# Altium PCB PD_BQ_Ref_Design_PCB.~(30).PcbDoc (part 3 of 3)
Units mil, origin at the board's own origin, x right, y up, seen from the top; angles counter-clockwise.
Board outline 2000 x 3702.76 mil, 4 copper layers (Top Layer, Signal Layer 1, Signal Layer 2, Bottom Layer), stack 61.2 mil thick; 124 components, 53 nets, 359 pads, 494 vias.
Unrouted connection lines stored in the file: 227.

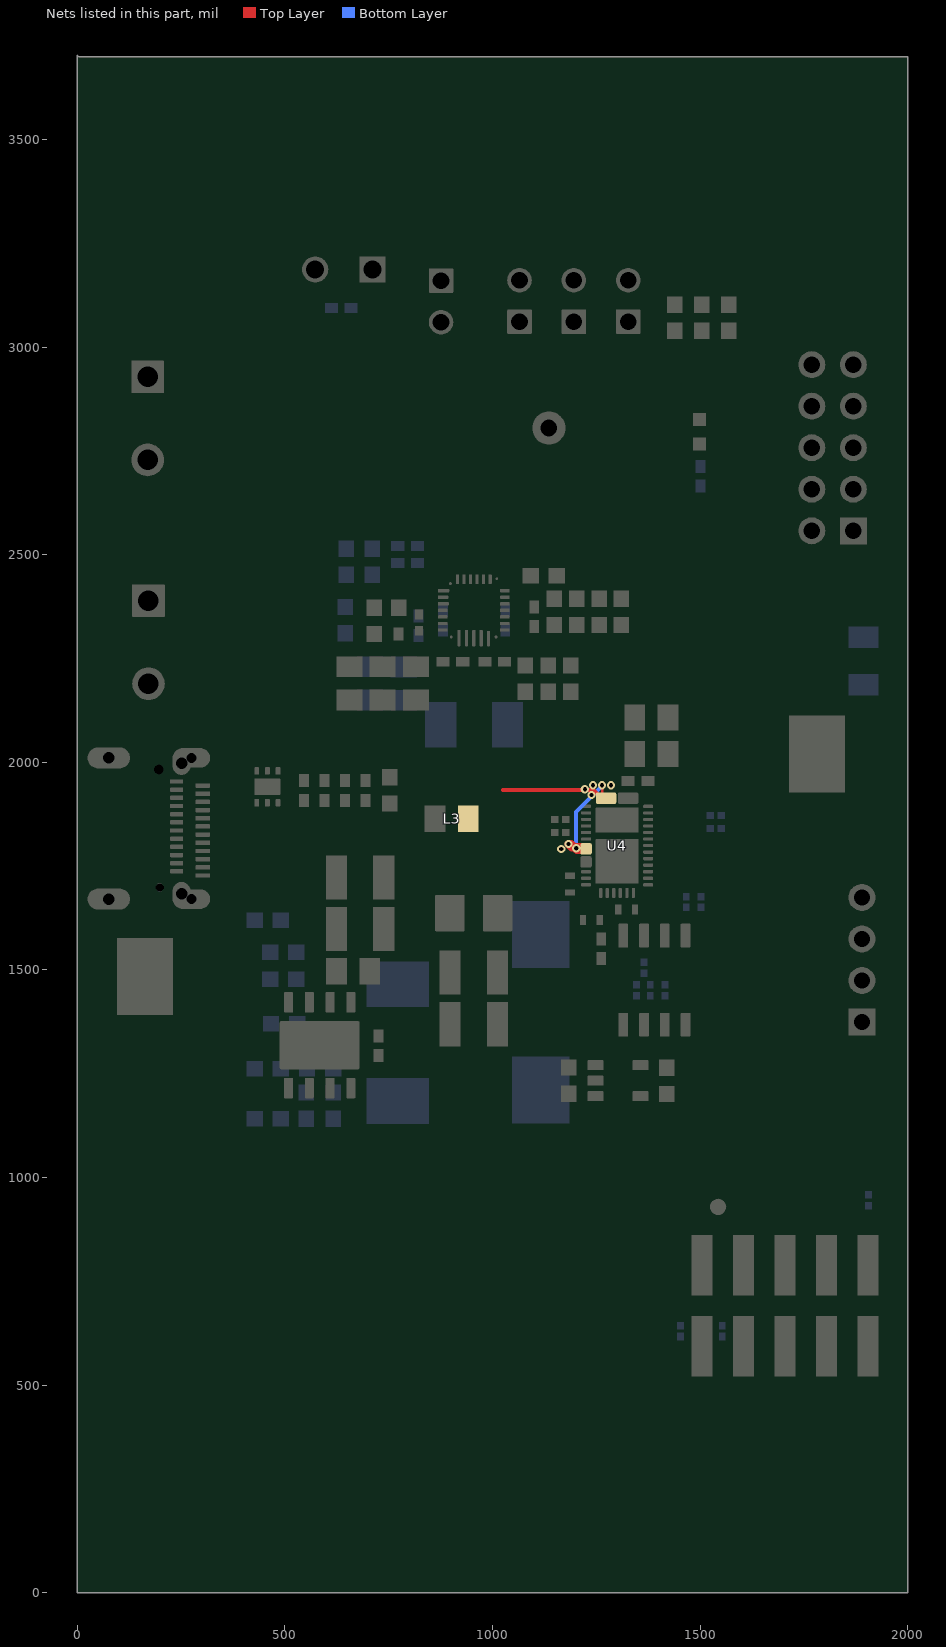
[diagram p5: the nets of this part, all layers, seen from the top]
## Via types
v1: diameter 20, hole 10, Top Layer to Bottom Layer, tented both sides, 445 vias
v2: diameter 23.62, hole 11.81, Top Layer to Bottom Layer, 24 vias
v3: diameter 30, hole 15, Top Layer to Bottom Layer, tented both sides, 12 vias
v4: diameter 19.68, hole 7.87, Top Layer to Bottom Layer, tented both sides, 10 vias
v5: diameter 20, hole 10, Top Layer to Bottom Layer, 3 vias

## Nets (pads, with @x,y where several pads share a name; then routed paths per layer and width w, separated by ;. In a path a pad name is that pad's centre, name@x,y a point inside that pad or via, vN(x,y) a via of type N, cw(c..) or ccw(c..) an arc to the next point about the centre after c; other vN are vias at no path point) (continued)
VBUS: L3.2 U4.23 U4.24 U4.25 U4.32 U4.33 U4.@1225.2,1791.52 U4.@1273.37,1913.57 | length 575.9
  Top Layer w6: v1@1200.79,1791.34 1225.02,1791.34 U4.@1225.2,1791.52 ; v1(1263.78,1944.88) 1263.78,1923.66 1273.62,1913.81 U4.@1273.37,1913.57
  Top Layer w10: 1025.59,1933.07 1222.44,1933.07 1242.98,1933.07 1262.49,1913.57 U4.@1273.37,1913.57
  Top Layer w20: v1@1210.63,1788.8 1203.32,1788.8 v1@1196.83,1795.3 ; U4.@1225.2,1791.52 1221.43,1795.3 v1@1196.83,1795.3 ; v1@1196.83,1795.3 1188.98,1803.15 v1(1183.07,1803.15) 1190.92,1795.3 v1@1196.83,1795.3
  Bottom Layer w10: v1@1200.79,1791.34 1200.79,1879.92 1263.78,1942.91 v1(1263.78,1944.88)
  other v1: 1165.35,1791.34 1201.76,1792.84 1238.19,1921.26 1222.44,1935.04 1242.13,1944.88 1285.43,1944.88
pads on no net: FID1.1 FID2.1 FID3.1 FID4.1 FID5.1 FID6.1 H1.1 H2.1 H3.1 H4.1 H5.0 H6.0 H7.0 H8.0 J3.1 J3.2 J3.3 J3.4 J3.7 J3.8 J5.4 J5.5 J5.6 J5.7 J5.8 J5.9 J6.A2 J6.A3 J6.A8 J6.A10 J6.A11 J6.ALIGN1 J6.ALIGN2 J6.B2 J6.B3 J6.B8 J6.B10 J6.B11 J7.1 SH-J1.0 SH-J2.0 U1.6 U1.7 U1.12 U1.21 U2.4 U3.9@583.66,1318.62 U4.6 U4.7 U4.13 U4.19 U4.36 U4.37 U6.7@439.96,1940.94 U6.7@475.39,1940.94

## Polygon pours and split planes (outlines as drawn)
NetC22_1 on Top Layer "TOP_LAYER_NETC22_1_P111" (solid, remove dead copper, pour order 111): 904.78,2306.69 854.73,2306.69 854.33,2307.09 854.33,2277.56 905.51,2277.56 904.78,2278.29
STAT on Top Layer "TOP_LAYER_STAT_P109" (solid, remove dead copper, pour order 109): 1003.94,2306.69 1003.94,2280.91 1005.32,2279.53 1041.34,2279.53 1041.34,2306.63 1040.88,2307.09 1040.2,2306.41 1004.63,2306.41
PPHV on Top Layer "TOP_LAYER_PPHV_P107" (solid, remove dead copper, pour order 107): 1006.6,2425.67 1006.17,2426.1 1006.17,2470.47 1045.28,2491.1 1046.22,2490.16 1055.12,2490.16 1055.12,2478.35 1039.37,2462.6 1039.37,2411.42 1041.14,2409.65 1019.69,2409.65 1019.69,2423.23 1017.24,2425.67
TS on Top Layer "TOP_LAYER_TS_P105" (solid, remove dead copper, pour order 105): 858.27,2462.6 891.62,2462.6 903.54,2450.67 903.54,2425.67 869.36,2425.67 869.08,2425.4 859.44,2435.04 858.27,2435.04
NetC1_2 on Top Layer "TOP_LAYER_NETC1_2_P103" (solid, remove dead copper, pour order 103): 966.54,2364.17 966.54,2322.83 1013.78,2322.83 1013.78,2364.17
NetC7_2 on Top Layer "TOP_LAYER_NETC7_2_P101" (solid, remove dead copper, pour order 101): 899.61,2364.17 899.61,2324.8 942.91,2324.8 942.91,2364.17
BAT on Top Layer "TOP_LAYER_BAT_P099" (solid, pour order 99): 775.59,2330.71 842.52,2330.71 842.52,2316.93 840.55,2314.96 775.59,2314.96 775.59,2330.47 775.35,2330.71
GND on Top Layer "tgaTOP_LAYER_GND_P081" (solid, pour order 97): 14.09,159.45 2014.09,159.45 2014.09,3507.87 14.09,3507.87
VBUS on Top Layer "Top Layer-VBUS" (solid, pour order 95): 1104.33,1929.13 1206.69,1929.13 1236.22,1899.61 1297.24,1899.61 1297.24,1994.09 1025.59,1994.09 956.69,1925.2 911.42,1925.2 911.42,1799.21 974.41,1799.21
NetC44_1 on Top Layer "Top Layer-NetC44_1" (solid, pour order 89): 433.07,1799.21 891.73,1799.21 891.73,1842.52 891.73,1925.2 793.31,1925.2 505.91,1925.2 494.09,1913.39 421.26,1913.39 397.64,1889.76 330.71,1889.76 330.71,1781.5 415.35,1781.5
SYS on Top Layer "Top Layer-SYS" (solid, pour order 40): 547.24,1527.56 596.46,1478.35 596.46,1433.07 620.08,1433.07 651.57,1464.57 655.51,1464.57 655.51,1779.53 464.57,1779.53 464.57,1669.29 547.24,1669.29
NetC25_2 on Top Layer "Top Layer-NetC25_2" (solid, pour order 85): 692.91,1204.72 728.35,1204.72 777.56,1253.94 777.56,1309.06 692.91,1309.06
SYS on Top Layer "Top Layer-SYS 1" (solid, pour order 72): 261.81,2187.01 865.07,2187.01 906.41,2228.35 906.41,2275.59 557.09,2275.59 535.43,2297.24 303.15,2297.24 224.41,2375.98 224.41,2444.88 202.76,2444.88 118.11,2444.88 118.11,2330.71
LDO_1V5 on Top Layer "NONET_L-01_P-001" (solid, pour order 77): 1273.62,1673.23 1273.62,1696.85 1311.02,1696.85 1311.02,1633.86 1295.28,1633.86 1295.28,1651.57
AGND on Top Layer "NONET_L-01_P-001" (solid, pour order 76): 1407.48,3066.93 1604.33,3066.93 1604.33,2988.19 1407.48,2988.19
AGND on Top Layer "NONET_L-01_P-001" (solid, pour order 75): 952.76,2429.13 940.94,2429.13 940.94,2490.16 1000,2490.16 1000,2429.13 972.44,2429.13 972.44,2456.69 952.76,2456.69
BAT on Top Layer "Top Layer-BAT" (solid, pour order 66): 565.01,2287.35 655.51,2287.4 832.68,2287.4 860.24,2314.96 889.76,2314.96 889.76,2338.58 852.36,2338.58 832.68,2318.9 803.15,2318.9 791.34,2330.71 694.88,2330.71 527.56,2498.03 527.56,2580.71 311.56,2796.71 110.24,2796.71 110.24,2673.23 281.5,2673.23 419.29,2535.43 419.29,2433.07
PPHV on Top Layer "Top Layer-PPHV" (solid, pour order 51): 1275.59,1899.61 1352.36,1899.61 1352.36,1980.32 1383.86,2011.81 1383.86,2181.1 1383.86,2364.17 1049.21,2364.17 1049.21,2287.4 1238.19,2287.4 1275.59,2250
no net on Top Layer "NONET_L-01_P-001" (solid, pour order 49): 1383.86,2181.1
no net on Top Layer "NONET_L-01_P-001" (solid, pour order 48): 1383.86,2161.42
PPHV on Top Layer "NONET_L-01_P-001" (solid, pour order 14): 1096.89,2338.58 1122.32,2364.02 1330.61,2364.02 1330.78,2309.06 1018.82,2309.06 1018.82,2338.58
REGN on Top Layer "NONET_L-01_P-001" (solid, pour order 32): 1026.69,2362.2 1054.25,2362.2 1081.81,2389.76 1081.81,2401.57 1111.34,2431.1 1111.34,2468.5 1071.97,2468.5 1052.28,2448.82 1052.28,2379.92 1042.44,2370.08 1026.69,2370.08
PMID on Top Layer "NONET_L-01_P-001" (solid, pour order 42): 1005.04,2275.59 1238.19,2275.59 1238.19,2200.79 1032.6,2200.79 1005.04,2228.35
P3V3 on Top Layer "NONET_L-01_P-001" (solid, pour order 30): 1212.6,1708.66 1198.82,1694.88 1198.82,1679.13 1206.69,1679.13 1228.35,1700.79 1228.35,1708.66
VBUS on Top Layer "NONET_L-01_P-001" (solid, pour order 20): 1218.5,1777.56 1218.5,1805.12 1200.79,1805.12 1188.98,1816.93 1149.61,1816.93 1149.61,1777.56
LDO_1V5 on Top Layer "NONET_L-01_P-001" (solid, pour order 31): 1311.02,1624.02 1311.02,1688.98 1273.62,1688.98 1273.62,1673.23 1293.31,1673.23 1293.31,1624.02
LDO_3V3 on Top Layer "NONET_L-01_P-001" (solid, pour order 29): 1265.75,1681.1 1271.65,1675.2 1271.65,1622.05 1251.97,1622.05 1251.97,1649.61 1251.97,1681.1
PP5V on Top Layer "NONET_L-01_P-001" (solid, pour order 28): 1263.78,1685.04
PP5V on Top Layer "Top Layer-PP5V" (solid, pour order 17): 970.47,1295.28 1110.24,1295.28 1110.24,1710.63 1145.67,1746.06 1238.19,1746.06 1238.19,1773.62 1157.48,1773.62 1137.61,1793.49 1039.55,1793.49 1017.72,1771.65 970.47,1724.41
NetC1_2 on Bottom Layer "NONET_L-01_P-001" (solid, pour order 44): 1000,2037.4 1000,2141.73 1044.41,2141.73 1044.41,2037.4
NetC7_2 on Bottom Layer "NONET_L-01_P-001" (solid, pour order 43): 913.39,2037.4 913.39,2141.73 867.24,2141.73 867.24,2037.4
GND on Bottom Layer "BOTTOM_LAYER_GND_P090" (solid, remove dead copper, pour order 90): -9.77,342.38 1990.23,342.38 1990.23,3342.38 -9.77,3342.38
SYS on Bottom Layer "Top Layer-SYS 1" (solid, pour order 87): 500,2187.01 865.07,2187.01 906.41,2228.35 906.41,2275.59 557.09,2275.59 535.43,2297.24 500,2297.24
SYS on Bottom Layer "Bottom Layer-SYS" (solid, pour order 74): 610.24,1881.89 610.24,2033.46 610.24,2277.56 500,2277.56 500,1984.25 500,1921.26 464.57,1885.83 464.57,1669.29 574.8,1669.29 574.8,1846.46
NetC25_2 on Bottom Layer "Bottom Layer-NetC25_2" (solid, pour order 84): 692.91,1125.98 960.63,1125.98 1187.01,1125.98 1187.01,1242.13 777.56,1242.13 777.56,1309.06 692.91,1309.06
NetU4_15 on Bottom Layer "NONET_L-01_P-001" (solid, pour order 78): 1247.84,1891.73 1247.84,1829.91 1352.05,1829.91 1352.37,1891.73
no net on Bottom Layer "NONET_L-01_P-001" (solid, pour order 37): 539.37,2372.05
PP5V on Bottom Layer "NONET_L-01_P-001" (solid, pour order 22): 970.47,1665.35 970.47,1446.85 1185.04,1446.85 1185.04,1665.35
VBUS on Bottom Layer "NONET_L-01_P-001" (solid, pour order 21): 1212.6,1777.56 1157.48,1777.56 1157.48,1891.73 1222.44,1956.69 1297.24,1956.69 1297.24,1899.61 1238.19,1899.61 1212.6,1874.02
AGND on Signal Layer 2 "SIGNAL_LAYER_2_AGND_P083" (solid, remove dead copper, pour order 83): 5.91,330.71 2005.91,330.71 2005.91,3330.71 5.91,3330.71
NetU4_15 on Signal Layer 2 "NONET_L-01_P-001" (solid, pour order 80): 1248.03,1890.37 1248.03,1830.71 1352.24,1830.89 1352.36,1890.37
NetC7_2 on Signal Layer 2 "NONET_L-01_P-001" (solid, pour order 45): 900.71,2218.5 873.15,2218.5 873.15,2250 900.71,2277.56 900.71,2354.33 942.05,2354.33 942.05,2261.81
NetC1_2 on Signal Layer 2 "NONET_L-01_P-001" (solid, pour order 46): 1010.94,2218.5 1038.5,2218.5 1038.5,2250 1010.94,2277.56 1010.94,2354.33 969.61,2354.33 969.61,2261.81
GND on Signal Layer 1 "SIGNAL_LAYER_1_GND_P082" (solid, pour order 82): 5.91,330.71 2005.91,330.71 2005.91,3330.71 5.91,3330.71
NetU4_15 on Signal Layer 1 "NONET_L-01_P-001" (solid, pour order 79): 1248.03,1891.73 1352.36,1891.73 1351.98,1891.35 1351.98,1830.89 1248.04,1830.89

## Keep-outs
Keep-Out Layer:
  text ".Layer_Name" at 582.91,-527.78 h60

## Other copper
Top Layer:
  pour cut-out: 1005.91,2029.53 1005.91,2149.61 905.51,2149.61 905.51,2029.53
  text ".Layer_Name" at 582.91,-527.78 h60
Signal Layer 1:
  pour cut-out: 860.24,2151.57 1051.18,2151.57 1051.18,2029.53 862.2,2029.53
Signal Layer 2:
  pour cut-out: 860.24,2188.98 1051.18,2188.98 1051.18,2027.56 862.2,2027.56
Bottom Layer:
  pour cut-out: 860.24,2153.54 860.24,2027.56 1051.18,2027.56 1051.18,2153.54
  text ".Layer_Name" at 582.91,-527.78 h60

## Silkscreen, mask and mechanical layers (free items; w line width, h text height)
Top Overlay:
  lines w5: 392.72,1996.06 392.72,2104.33 392.72,2549.21 1243.11,2549.21 1498.03,2549.21 1498.03,1096.46 392.72,1096.46 392.72,1275.59 392.72,1999.02 ; 836.61,2025.59 852.36,2041.34 866.14,2055.12 866.14,2196.85 879.92,2210.63 ; 1033.46,2210.63 1043.31,2200.79 1043.31,2055.12 1068.9,2029.53 1075.79,2022.64 ; 1120.08,2295.28 1133.86,2281.5 1248.03,2281.5 ; 1188.98,2429.13 1210.63,2450.79 ; 1220.47,2429.13 1244.09,2452.76 ; 1267.72,2429.13 1293.31,2454.72 ; 1320.87,2431.1 1346.46,2456.69 ; 1210.63,2450.79 1210.63,2450.79
  text "'.PRJ_Number'.PCB_Rev" at 1427.17,3212.6 h108.27
  text "up to 5A" at 51.18,3051.18 h60
  text "EXT_TS" at 548.34,2978.23 h60
  text "2S" at 1047.62,2960.77 h60
  text "4S" at 1312.12,2959.76 h60
  text "3S" at 1179.51,2959.17 h60
  text "TS" at 855.43,2953.85 h60
  text "GND" at 431.98,2859.36 h60 r90
  text "STAT" at 1302.28,2818.02 h60
  text "PPHV" at 1064.09,2644.8 h60
  text "BATT" at 443.79,2627.08 h60 r90
  text "up to 10A" at 59.06,2515.93 h60
  text "SYS" at 447.72,2341.65 h60 r90
  text "USB2ANY" at 1694.99,2239.28 h60
  text "Connector" at 1628.06,2185.15 h60
  text "GND" at 445.76,2134.95 h60 r90
  text "GND" at 1751.09,1794.4 h60
  text "GND" at 85.74,1257.98 h60
  text "Aardvark" at 1661.53,956.8 h60
  text "Connector" at 1628.06,896.76 h60
  text "Total Solution Size" at 397.75,879.05 h60
  text "USB-PD-CHG-EVM-01" at 363.91,659.45 h108
  text ".Layer_Name" at 582.91,-527.78 h60
Bottom Overlay:
  text ".Layer_Name" at 582.91,-527.78 h60
Top Paste:
  text ".Layer_Name" at 582.91,-527.78 h60
Bottom Paste:
  text ".Layer_Name" at 582.91,-527.78 h60
Top Solder:
  text ".Layer_Name" at 582.91,-527.78 h60
  text ".Layer_Name" at 582.91,-527.78 h60
Bottom Solder:
  text ".Layer_Name" at 582.91,-527.78 h60
Drill Guide:
  text ".Layer_Name" at 582.91,-527.78 h60
M1 Board Outline:
  lines w10: 5.91,330.71 5.91,3330.71 2005.91,3330.71 2005.91,330.71 5.91,330.71
  text ".Layer_Name" at 582.91,-527.78 h60
M2 Board Dimensions:
  rectangle: 5.91,55.71 130.91,180.71
  rectangle: 130.91,-69.29 505.91,55.71
  lines w7: 5.91,55.71 1005.91,55.71 ; 130.91,-69.29 130.91,180.71 ; 255.91,-69.29 255.91,180.71 ; 505.91,-69.29 505.91,180.71 ; 755.91,-69.29 755.91,180.71 ; 5.91,-69.29 1005.91,-69.29 1005.91,180.71 5.91,180.71 5.91,-69.29
  text ".Layer_Name" at 582.91,-527.78 h60
M3 3D STEP Top:
  text ".Layer_Name" at 582.91,-527.78 h60
M4 3D STEP Bottom:
  text ".Layer_Name" at 582.91,-527.78 h60
M5 Assembly Top:
  lines w10: -286.09,-599.46 6313.91,-599.46 ; -286.09,-396.12 6315.91,-396.12 ; -286.09,-192.79 -286.09,-802.79 3718.91,-802.79 6315.91,-802.79 6315.91,-192.79 -285.59,-192.79 -285.59,-802.79 1289.91,-802.79 ; 2178.91,-802.79 2178.91,-192.79 ; 3445.91,-396.12 3445.91,-192.79 ; 4285.91,-396.12 4285.91,-192.79 ; 4907.91,-809.29 4907.91,-606.46
  text "COMPONENTS MARKED 'DNP' SHOULD NOT BE POPULATED." at 1159.41,12.21 h60
  text "ASSEMBLY VARIANT:" at 1158.91,-103.29 h60
  text ".VariantName" at 2194.91,-103.29 h60
  text "PCB VIEWED FROM TOP SIDE" at -222.59,-324.96 h60
  text "BOARD #:" at 2253.91,-324.96 h60
  text ".PRJ_Number" at 2799.41,-324.96 h60
  text "REV:" at 3643.91,-324.96 h60
  text ".PCB_Rev" at 3935.41,-324.96 h60
  text "SVN REV:" at 4481.91,-324.96 h60
  text ".VersionControl_RevNumber" at 4987.91,-324.96 h60
  text "TID #:" at 2253.91,-528.29 h60
  text ".TID" at 2799.41,-528.29 h60
  text "PLOT NAME =" at -222.59,-733.63 h60
  text ".plot_File_Name" at 582.91,-733.63 h60
  text "GENERATED    :" at 2255.91,-733.63 h60
  text ".Print_Date" at 3125.41,-733.63 h60
  text ".Print_Time" at 3854.41,-733.63 h60
  text "TEXAS INSTRUMENTS" at 5118.91,-733.63 h60
M6 Assembly Bottom:
  lines w10: -286.59,-396.62 6315.41,-396.62 ; -284.59,-599.96 6315.41,-599.96 ; 1121.41,-809.79 1121.41,-606.96 ; 1743.41,-396.62 1743.41,-193.29 ; 2583.41,-396.62 2583.41,-193.29 ; 3850.41,-803.29 3850.41,-193.29 ; 4739.41,-803.29 6314.91,-803.29 6314.91,-193.29 -286.59,-193.29 -286.59,-803.29 2310.41,-803.29 6315.41,-803.29 6315.41,-193.29
  text "COMPONENTS MARKED 'DNP' SHOULD NOT BE POPULATED." at 6107.91,12.71 h60
  text ".VariantName" at 5063.91,-103.29 h60
  text "ASSEMBLY VARIANT:" at 6102.91,-103.29 h60
  text ".VersionControl_RevNumber" at 1041.41,-325.46 h60
  text "SVN REV:" at 1547.41,-325.46 h60
  text ".PCB_Rev" at 2093.91,-325.46 h60
  text "REV:" at 2385.41,-325.46 h60
  text ".PRJ_Number" at 3229.91,-325.46 h60
  text "BOARD #:" at 3775.41,-325.46 h60
  text "PCB VIEWED FROM BOTTOM SIDE" at 6251.91,-325.46 h60
  text ".TID" at 3229.91,-528.79 h60
  text "TID #:" at 3775.41,-528.79 h60
  text "TEXAS INSTRUMENTS" at 910.41,-734.13 h60
  text ".Print_Time" at 2174.91,-734.13 h60
  text ".Print_Date" at 2903.91,-734.13 h60
  text "GENERATED    :" at 3773.41,-734.13 h60
  text ".plot_File_Name" at 5446.41,-734.13 h60
  text "PLOT NAME =" at 6251.91,-734.13 h60
M9 Title Sheet:
  drawing of 57 lines, arcs and shapes, not listed
  text "1" at 745.74,8367.21 h70
  text "2" at 3241.41,8367.21 h70
  text "3" at 5730.75,8367.21 h70
  text "4" at 8237.42,8367.21 h70
  text "5" at 10736.41,8367.21 h70
  text "6" at 13241.41,8367.21 h70
  text "A" at -410.59,7224.21 h70
  text "A" at 14389.41,7224.21 h70
  text "B" at -410.59,4844.21 h70
  text "B" at 14389.41,4844.21 h70
  text "C" at -410.59,2469.21 h70
  text "C" at 14389.41,2469.21 h70
  text "PROJECT TITLE:" at 11349.41,608.21 h45
  text ".PRJ_Title" at 11399.41,474.88 h70
  text "DESIGNED FOR:" at 11349.41,307.21 h45
  text ".PRJ_Customer" at 11399.41,167.21 h70
  text "D" at -410.59,99.21 h70
  text "D" at 14389.41,99.21 h70
  text "FILE NAME:" at 11349.41,7.21 h45
  text ".PCB_File_Name_No_Path" at 11399.41,-112.79 h70
  text "Texas Instruments (TI) and/or its licensors do not warrant the accuracy or completeness of this specification" at 6379.91,-274.63 h45
  text "ENGINEER:" at 11349.41,-282.79 h45
  text "LAYOUT BY:" at 12854.41,-282.79 h45
  text "or any information contained therein. TI and/or its licensors do not warrant that this design will meet" at 6334.92,-387.3 h45
  text ".PRJ_Engineer" at 11399.41,-437.78 h70
  text ".PCB_Layout" at 12904.91,-437.78 h70
  text "the specifications, will be suitable for your application or fit for any particular purpose, or will operate in" at 6334.92,-499.96 h45
  text ".Layer_Name" at 582.91,-527.78 h60
  text "ALTIUM DESIGNER VERSION:" at 12854.41,-592.79 h45
  text "an implementation. TI and/or its licensors do not warrant that the design is production worthy. You should" at 6334.92,-612.63 h45
  text "completely validate and test your design implementation to confirm the system functionality for your application." at 6379.91,-725.29 h45
  text ".print_Scale" at 11399.41,-726.12 h70
  text ".Application_BuildNumber" at 12904.91,-726.12 h70
  text "1" at 745.74,-932.79 h70
  text "2" at 3241.41,-932.79 h70
  text "3" at 5730.75,-932.79 h70
  text "4" at 8237.42,-932.79 h70
  text "5" at 10736.41,-932.79 h70
  text "6" at 13241.41,-932.79 h70
M10 Fab Notes:
  drawing of 189 lines, arcs and shapes, not listed
  text "DESIGN INFORMATION" at 12387.92,6686.88 h60
  text "MIN. TRACK WIDTH:" at 11743.36,6554.76 h60
  text "8" at 12839.61,6554.76 h60
  text "MIL" at 12994.36,6554.76 h60
  text "MIN. CLEARANCE:" at 11743.36,6430.63 h60
  text "0.2" at 12779.61,6430.63 h60
  text "mm" at 12994.36,6430.63 h60
  text "MIN. VIA PAD SIZE:" at 11743.36,6306.5 h60
  text "24" at 12809.62,6306.51 h60
  text "MIL" at 12994.36,6306.5 h60
  text "0.05mm (2MIL)" at 12438.37,6176.61 h60
  text "MINIMUM ANNULAR RING" at 11414.13,6168.38 h60
  text "EXTERNAL" at 13146.37,6168.38 h60
  text "PER" at 11614.13,6058.26 h60
  text "IPC-D-275 CLASS 2 LEVEL C" at 11834.13,6058.25 h60
  text "MIL, HOLES" at 13322.36,5957.78 h60
  text "+/-" at 12929.91,5949.19 h60
  text "+/-" at 13783.91,5949.19 h60
  text "REGISTRATION TOLERANCES:" at 11414.13,5948.13 h60
  text "METAL" at 12613.91,5948.13 h60
  text "5" at 13190.11,5948.13 h60
  text "3" at 14023.11,5948.13 h60
  text "MIL" at 14139.36,5948.13 h60
  text "HOLE SIZE TOLERANCE (UNLESS OTHERWISE SPECIFIED):" at 11414.13,5849.81 h60
  text "+/-" at 13783.91,5846.94 h60
  text "3" at 14023.11,5845.88 h60
  text "MIL" at 14139.36,5845.88 h60
  text "MATERIAL:" at 11339.37,5708.23 h60
  text "FR-4 High Tg" at 12325.81,5579.7 h60
  text "X" at 12181.37,5571.72 h60
  text "FR-408" at 11760.37,5567.2 h60
  text "OTHER" at 13248.37,5567.2 h60
  text "62 MIL (1.6mm) +/-10%" at 12080.47,5424.17 h60
  text "X" at 11960.37,5421.72 h60
  text "THICKNESS:" at 11414.13,5415.95 h60
  text "OTHER" at 13365.37,5415.95 h60
  text "TOLERANCE:" at 11414.13,5277.63 h60
  text "X" at 12262.37,5277.63 h60
  text "ANSI IPC-6012 TYPE 3 CLASS 2" at 12440.38,5277.63 h60
  text "OTHER +/-" at 12440.37,5133.44 h60
  text "BOW & TWIST:" at 11414.13,4988.25 h60
  text "X" at 12262.37,4988.25 h60
  text "ANSI IPC-6012 TYPE 3 CLASS 2" at 12440.38,4988.25 h60
  text "OTHER +/-" at 12440.37,4841.56 h60
  text "DRILLING:" at 11339.37,4710.94 h60
  text "NC_DRILL FILES" at 13100.36,4605.75 h60
  text "REFERENCE:" at 11414.13,4601.81 h60
  text "X" at 12071.37,4601.72 h60
  text "AS SHOWN" at 12249.36,4601.81 h60
  text "X" at 12972.37,4601.81 h60
  text "OTHER" at 13398.37,4459.56 h60
  text "PTH COPPER THICKNESS:" at 11413.81,4456.03 h60
  text "X" at 12553.05,4456.03 h60
  text "20-30 um" at 12681.04,4456.03 h60
  text "BOARD FINISH:" at 11339.37,4308.43 h60
  text "SILKSCREEN:" at 11494.59,4198.31 h60
  text "X" at 12452.37,4198.31 h60
  text "TOP" at 12569.36,4198.31 h60
  text "X" at 12962.37,4198.31 h60
  text "BOTTOM" at 13080.36,4198.31 h60
  text "SILKSCREEN COLOR:" at 11494.59,4043.12 h60
  text "X" at 12451.37,4043.12 h60
  text "WHITE" at 12569.36,4043.12 h60
  text "OTHER" at 13080.36,4043.12 h60
  text "X" at 12582.37,3899.67 h60
  text "GREEN" at 12700.36,3899.67 h60
  text "OTHER" at 13318.37,3899.67 h60
  text "SOLDER RESIST COLOR:" at 11494.59,3892.8 h60
  text "X" at 12582.37,3745.42 h60
  text "MATTE" at 12700.36,3745.42 h60
  text "SEMI-GLOSS" at 13317.91,3744.78 h60
  text "IMMERSION GOLD (ENIG)" at 12400.36,3572.65 h60
  text "ENEPIG" at 13737.91,3565.43 h60
  text "SURFACE FINISH:" at 11339.37,3564.43 h60
  text "X" at 12222.37,3564.43 h60
  text "IMM. TIN/SILVER OR EQUIV" at 11668.91,3427.11 h60
  text "OTHER" at 13100.37,3423.17 h60
  text "ARRAY/PANEL:" at 11339.37,3267.8 h60
  text "CUT AND TRIM PER M1 BOARD OUTLINE" at 12400.37,3259.57 h60
  text "N.C. ROUTE" at 12400.36,3123.61 h60
  text "X" at 13088.37,3123.61 h60
  text "V. SCORE" at 13266.37,3123.61 h60
  text "CERTIFICATION:" at 11339.37,2994.48 h60
  text "MATERIALS AND WORKMANSHIP FOR ALL PCBS" at 12064.37,2994.48 h60
  text "TO MEET OR EXCEED THE REQUIREMENTS OF:" at 12064.37,2900.42 h60
  text "X" at 11701.87,2771.79 h60
  text "ANSI IPC-A-600F CLASS ->" at 11829.87,2771.79 h60
  text "X" at 13477.87,2771.79 h60
  text "2" at 13587.87,2771.79 h60
  text "1" at 13272.87,2770.29 h60
  text "3" at 13941.87,2770.29 h60
  text "X" at 12513.87,2624.1 h60
  text "RoHS" at 12641.87,2624.1 h60
  text "OTHER" at 13286.27,2624.1 h60
  text "PER ORDER" at 13683.33,2624.1 h60
  text "ALL BOARDS MUST MEET OR EXCEED UL94-V0 REQUIREMENTS." at 11366.91,2470.28 h60
  text "PCB MUST BEAR THE UL94V-0 UL REGISTERED MATERIAL ID NUMBER" at 11366.91,2354.21 h60
  text "ADDITIONAL REQUIREMENTS:" at 11339.37,2184.79 h60
  text "MICROSECTION:" at 11414.13,2077.66 h60
  text "YES" at 12319.87,2077.66 h60
  text "REQUIRED" at 13181.36,1933.33 h60
  text "BARE BOARD ELEC. TEST:" at 11414.13,1930.47 h60
  text "NONE" at 12719.87,1930.47 h60
  text "X" at 13063.37,1930.47 h60
  text "PER ORDER" at 13773.37,1930.47 h60
  text "XX MIL VIAS REQUIRE NON-CONDUCTIVE FILL AND PLANARIZE" at 11582.28,1725.53 h59
  text "XX MIL VIAS REQUIRE CONDUCTIVE FILL AND PLANARIZE" at 11590.28,1621.55 h60
  text "OUTER XX MIL TRACES REQUIRE 50 OHM SINGLE-ENDED IMPEDANCE" at 11589.3,1458.17 h58
  text "LAYER 2 & 3 (INNER LAYERS) XX MIL WIDE, XX MIL SPACE / TRACES REQUIRE 100 OHM DIFFERENTIAL IMPEDANCE" at 11581.3,1222.45 h60
  text ".Layer_Name" at 582.91,-527.78 h60
M11 Gerber Information:
  lines w10: -286.09,-599.46 6313.91,-599.46 ; -286.09,-396.12 6315.91,-396.12 ; -286.09,-192.79 -286.09,-802.79 3718.91,-802.79 6315.91,-802.79 6315.91,-192.79 -285.59,-192.79 -285.59,-802.79 1289.91,-802.79 ; 2178.91,-802.79 2178.91,-192.79 ; 3445.91,-396.12 3445.91,-192.79 ; 4285.91,-396.12 4285.91,-192.79 ; 4907.91,-809.29 4907.91,-606.46
  text "ALL ARTWORK VIEWED FROM TOP SIDE" at -222.59,-324.96 h60
  text "BOARD #:" at 2253.91,-324.96 h60
  text ".PRJ_Number" at 2799.41,-324.96 h60
  text "REV:" at 3643.91,-324.96 h60
  text ".PCB_Rev" at 3935.41,-324.96 h60
  text "SVN REV:" at 4481.91,-324.96 h60
  text ".VersionControl_RevNumber" at 4987.91,-324.96 h60
  text "LAYER NAME =" at -222.59,-527.78 h60
  text "TID #:" at 2253.91,-528.29 h60
  text ".TID" at 2799.41,-528.29 h60
  text "PLOT NAME =" at -222.59,-733.63 h60
  text ".plot_File_Name" at 582.91,-733.63 h60
  text "GENERATED    :" at 2255.91,-733.63 h60
  text ".Print_Date" at 3125.41,-733.63 h60
  text ".Print_Time" at 3854.41,-733.63 h60
  text "TEXAS INSTRUMENTS" at 5118.91,-733.63 h60
M12 Stackup:
  drawing of 295 lines, arcs and shapes, not listed
  text "Layer" at 9817.5,7958.15 h60
  text "Name" at 10227.41,7958.15 h60
  text "Material" at 11167.15,7958.15 h60
  text "Thickness" at 12026.92,7958.15 h60
  text "Constant" at 12676.76,7958.15 h60
  text "Board Layer Stack" at 13246.62,7958.15 h60
  text "1" at 9817.5,7838.15 h60
  text "Top Overlay" at 10227.41,7838.15 h60
  text "2" at 9817.5,7718.15 h60
  text "Top Solder" at 10227.41,7718.15 h60
  text "Solder Resist" at 11167.15,7718.15 h60
  text "0.40mil" at 12026.92,7718.15 h60
  text "3.5" at 12676.76,7718.15 h60
  text "3" at 9817.5,7598.15 h60
  text "Top Layer" at 10227.41,7598.15 h60
  text "Copper" at 11167.15,7598.15 h60
  text "2.80mil" at 12026.92,7598.15 h60
  text "4" at 9817.5,7478.15 h60
  text "Dielectric 1" at 10227.41,7478.15 h60
  text "FR-4 High TG" at 11167.15,7478.15 h60
  text "12.00mil" at 12026.92,7478.15 h60
  text "4.2" at 12676.76,7478.15 h60
  text "5" at 9817.5,7358.15 h60
  text "Signal Layer 1" at 10227.41,7358.15 h60
  text "Copper" at 11167.15,7358.15 h60
  text "2.80mil" at 12026.92,7358.15 h60
  text "6" at 9817.5,7238.15 h60
  text "Dielectric2" at 10227.41,7238.15 h60
  text "FR-4 High TG" at 11167.15,7238.15 h60
  text "26.00mil" at 12026.92,7238.15 h60
  text "4.2" at 12676.76,7238.15 h60
  text "7" at 9817.5,7118.15 h60
  text "Signal Layer 2" at 10227.41,7118.15 h60
  text "Copper" at 11167.15,7118.15 h60
  text "2.80mil" at 12026.92,7118.15 h60
  text "8" at 9817.5,6998.15 h60
  text "Dielectric3" at 10227.41,6998.15 h60
  text "FR-4 High TG" at 11167.15,6998.15 h60
  text "12.00mil" at 12026.92,6998.15 h60
  text "4.2" at 12676.76,6998.15 h60
  text "9" at 9817.5,6878.15 h60
  text "Bottom Layer" at 10227.41,6878.15 h60
  text "Copper" at 11167.15,6878.15 h60
  text "2.80mil" at 12026.92,6878.15 h60
  text "10" at 9817.5,6758.15 h60
  text "Bottom Solder" at 10227.41,6758.15 h60
  text "Solder Resist" at 11167.15,6758.15 h60
  text "0.40mil" at 12026.92,6758.15 h60
  text "3.5" at 12676.76,6758.15 h60
  text "11" at 9817.5,6638.15 h60
  text "Bottom Overlay" at 10227.41,6638.15 h60
  text ".Layer_Name" at 582.91,-527.78 h60
M13 Component Bodies Top:
  text ".Layer_Name" at 582.91,-527.78 h60
M14 Component Bodies Bottom:
  text ".Layer_Name" at 582.91,-527.78 h60
M15 Courtyards Top:
  text ".Layer_Name" at 582.91,-527.78 h60
M16 Courtyards Bottom:
  text ".Layer_Name" at 582.91,-527.78 h60
Drill Drawing:
  drawing of 152 lines, arcs and shapes, not listed
  text "Symbol" at 5366.5,3847.99 h72
  text "Quantity" at 5667.06,3847.99 h72
  text "Finished Hole Size" at 5999.06,3847.99 h72
  text "Plated" at 6635.63,3847.99 h72
  text "Hole Type" at 6894.77,3847.99 h72
  text "Drill Layer Pair" at 7269.93,3847.99 h72
  text "Hole Tolerance" at 7994.26,3847.99 h72
  text "1" at 5667.06,3723.67 h60
  text "23.62mil (0.600mm)" at 5999.06,3723.67 h60
  text "NPTH" at 6635.63,3723.67 h60
  text "Round" at 6894.77,3723.67 h60
  text "Top Layer - Bottom Layer" at 7269.93,3723.67 h60
  text "+/-1.18mil" at 7994.26,3723.67 h60
  text "10" at 5667.06,3599.35 h60
  text "7.87mil (0.200mm)" at 5999.06,3599.35 h60
  text "PTH" at 6635.63,3599.35 h60
  text "Round" at 6894.77,3599.35 h60
  text "Top Layer - Bottom Layer" at 7269.93,3599.35 h60
  text "448" at 5667.06,3475.03 h60
  text "10.00mil (0.254mm)" at 5999.06,3475.03 h60
  text "PTH" at 6635.63,3475.03 h60
  text "Round" at 6894.77,3475.03 h60
  text "Top Layer - Bottom Layer" at 7269.93,3475.03 h60
  text "24" at 5667.06,3350.71 h60
  text "11.81mil (0.300mm)" at 5999.06,3350.71 h60
  text "PTH" at 6635.63,3350.71 h60
  text "Round" at 6894.77,3350.71 h60
  text "Top Layer - Bottom Layer" at 7269.93,3350.71 h60
  text "12" at 5667.06,3226.39 h60
  text "15.00mil (0.381mm)" at 5999.06,3226.39 h60
  text "PTH" at 6635.63,3226.39 h60
  text "Round" at 6894.77,3226.39 h60
  text "Top Layer - Bottom Layer" at 7269.93,3226.39 h60
  text "4" at 5667.06,3102.07 h60
  text "39.37mil (1.000mm)" at 5999.06,3102.07 h60
  text "PTH" at 6635.63,3102.07 h60
  text "Round" at 6894.77,3102.07 h60
  text "Top Layer - Bottom Layer" at 7269.93,3102.07 h60
  text "19" at 5667.06,2977.75 h60
  text "40.00mil (1.016mm)" at 5999.06,2977.75 h60
  text "PTH" at 6635.63,2977.75 h60
  text "Round" at 6894.77,2977.75 h60
  text "Top Layer - Bottom Layer" at 7269.93,2977.75 h60
  text "2" at 5667.06,2853.43 h60
  text "43.31mil (1.100mm)" at 5999.06,2853.43 h60
  text "PTH" at 6635.63,2853.43 h60
  text "Round" at 6894.77,2853.43 h60
  text "Top Layer - Bottom Layer" at 7269.93,2853.43 h60
  text "4" at 5667.06,2729.11 h60
  text "49.21mil (1.250mm)" at 5999.06,2729.11 h60
  text "PTH" at 6635.63,2729.11 h60
  text "Round" at 6894.77,2729.11 h60
  text "Top Layer - Bottom Layer" at 7269.93,2729.11 h60
  text "4" at 5667.06,2604.79 h60
  text "125.98mil (3.200mm)" at 5999.06,2604.79 h60
  text "PTH" at 6635.63,2604.79 h60
  text "Round" at 6894.77,2604.79 h60
  text "Top Layer - Bottom Layer" at 7269.93,2604.79 h60
  text "1" at 5667.06,2480.47 h60
  text "19.69mil (0.500mm)" at 5999.06,2480.47 h60
  text "NPTH" at 6635.63,2480.47 h60
  text "Slot" at 6894.77,2480.47 h60
  text "Top Layer - Bottom Layer" at 7269.93,2480.47 h60
  text "+/-1.18mil" at 7994.26,2480.47 h60
  text "2" at 5667.06,2356.15 h60
  text "23.62mil (0.600mm)" at 5999.06,2356.15 h60
  text "PTH" at 6635.63,2356.15 h60
  text "Slot" at 6894.77,2356.15 h60
  text "Top Layer - Bottom Layer" at 7269.93,2356.15 h60
  text "+/-1.97mil" at 7994.26,2356.15 h60
  text "2" at 5667.06,2231.83 h60
  text "27.56mil (0.700mm)" at 5999.06,2231.83 h60
  text "PTH" at 6635.63,2231.83 h60
  text "Slot" at 6894.77,2231.83 h60
  text "Top Layer - Bottom Layer" at 7269.93,2231.83 h60
  text "+/-1.97mil" at 7994.26,2231.83 h60
  text "2" at 5667.06,2107.51 h60
  text "27.56mil (0.700mm)" at 5999.06,2107.51 h60
  text "PTH" at 6635.63,2107.51 h60
  text "Slot" at 6894.77,2107.51 h60
  text "Top Layer - Bottom Layer" at 7269.93,2107.51 h60
  text "+/-1.97mil" at 7994.26,2107.51 h60
  text "535 Total" at 5667.06,1983.19 h60
  text "Slot definitions :" at 5366.5,1896.16 h60
  text "Routed Path Length" at 5817.21,1896.16 h60
  text "= Calculated from tool start centre position to tool end centre position." at 6356.95,1896.16 h60
  text "Hole Length" at 5817.21,1846.43 h60
  text "= Routed Path Length + Tool Size = Slot length as defined in the PCB layout" at 6157.15,1846.43 h60
  text ".Layer_Name" at 582.91,-527.78 h60
M17 Embedded Cavity:
  text ".Layer_Name" at 582.91,-527.78 h60
M18 Embedded Assembly:
  text ".Layer_Name" at 582.91,-527.78 h60
M19 Embedded Keepout:
  text ".Layer_Name" at 582.91,-527.78 h60

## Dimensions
1498.03,2549.21 to 1498.03,1096.46 on Top Overlay
392.72,1096.46 to 1498.03,1096.46 on Top Overlay
5.91,-69.29 to 1005.91,-69.29 on M2 Board Dimensions
5.91,330.71 to 2.76,3700 on M2 Board Dimensions
5.91,330.71 to 2000,0 on M2 Board Dimensions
